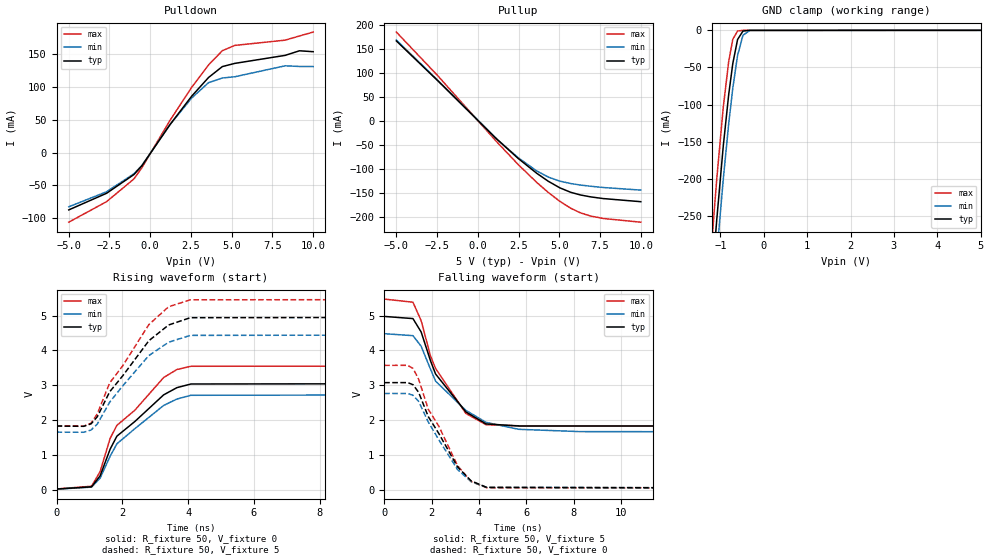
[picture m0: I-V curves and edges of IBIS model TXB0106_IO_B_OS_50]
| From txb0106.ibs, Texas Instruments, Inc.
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[Model]   TXB0106_IO_B_OS_50
Model_type  I/O
Vinl=1.575
Vinh=3.575
Enable   Active-High
Vref =   0
Rref =   1e6
Cref =   15p
Vmeas =   2.5
| variable   typ   min   max
C_comp   13.18pF   11.07pF   15.52pF
| C_pullup   13.01pF   10.37pF   16.24pF
| C_pulldown   13.28pF   11.92pF   15.14pF
| C_tri-state   13.18pF   11.07pF   15.52pF
[Temperature Range]   40   100   -40
| Ambient temperature   25   85   -40
[Voltage range]   5   4.5   5.5
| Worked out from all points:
|   slope of the pulldown table from 0 to 0.75 V, typ, clamps not added: 27.3 ohm
|   slope of the pullup table from 0 to 0.75 V, typ, clamps not added: 29.6 ohm
|   GND clamp passes 1 mA (typ) near -0.48 V on its own axis
|   rising waveform, R_fixture 50, V_fixture 0: 20-80 % time 1.49ns typ, 1.5ns min, 1.47ns max; typ from 0.021 V to 3.08 V
|   falling waveform, R_fixture 50, V_fixture 5: 20-80 % time 1.5ns typ, 1.86ns min, 1.45ns max; typ from 4.98 V to 1.83 V
|   rising waveform, R_fixture 50, V_fixture 5: 20-80 % time 1.45ns typ, 1.44ns min, 1.42ns max; typ from 1.83 V to 4.98 V
|   falling waveform, R_fixture 50, V_fixture 0: 20-80 % time 1.47ns typ, 1.42ns min, 1.46ns max; typ from 3.08 V to 0.021 V
[GND Clamp]
| TXB0104_IO_B_OS_50
|   Voltage   I(typ)   I(min)   I(max)
-5V       -4.543A    -4.41A     -4.793A
-1.245V   -376.1mA   -424.3mA   -324mA
-1.21V    -348.4mA   -396.7mA   -295.4mA
-1.14V    -294.9mA   -343.1mA   -240.7mA
-1.085V   -254.9mA   -302.6mA   -200.3mA
-935mV    -155.8mA   -200.5mA   -103.7mA
-810mV    -86.64mA   -126.1mA   -42.07mA
-715mV    -44.62mA   -77.69mA   -11.99mA
-605mV    -12.35mA   -33.78mA   -908.3uA
-480mV    -968.2uA   -6.599mA   -13.77uA
-325mV    -13.63uA   -271.7uA   -22.36nA
5V        1.525nA    314.6nA    140.3pA
[Pulldown]
| TXB0104_IO_B_OS_50
|   Voltage   I(typ)   I(min)   I(max)
-5V       -87.47mA   -82.76mA   -106.2mA
-2.675V   -62.09mA   -59.78mA   -74.83mA
-1V       -33.59mA   -32.37mA   -40.27mA
-510mV    -20.09mA   -19.73mA   -23.11mA
1.21V     42.51mA    42.31mA    48.84mA
2.55V     86.05mA    83.26mA    99.58mA
3.58V     114.4mA    106.5mA    133.5mA
4.425V    131mA      113.6mA    155.2mA
5.19V     135.9mA    115.5mA    163.3mA
8.28V     148.1mA    132.2mA    171.3mA
9.16V     155.1mA    131.2mA    177.7mA
10V       153.7mA    131.1mA    183.6mA
[Pullup]
| TXB0104_IO_B_OS_50
|   Voltage   I(typ)   I(min)   I(max)
-5V       167.3mA    169.2mA    185.8mA
-2.47V    84.58mA    85.55mA    95.09mA
1.16V     -37.5mA    -37.56mA   -43.27mA
2.475V    -77.97mA   -76.43mA   -90.69mA
3.615V    -109mA     -104.1mA   -128.1mA
4.33V     -125.8mA   -117mA     -149.2mA
5.035V    -139.4mA   -125.4mA   -167.6mA
5.7V      -148.7mA   -130.4mA   -182mA
6.305V    -154.3mA   -133.6mA   -191.7mA
6.93V     -158.3mA   -136.1mA   -198.3mA
7.705V    -161.8mA   -138.7mA   -203.4mA
10V       -168.3mA   -144.1mA   -211.1mA
[Ramp]
| TXB0104_IO_B_OS_50
| variable   typ   min   max
dV/dt_r   1.84/1.49E-09   1.65/1.50E-09   2.14/1.47E-09
dV/dt_f   1.89/1.50E-09   1.70/1.86E-09   2.19/1.45E-09
R_load = 50
[Rising Waveform]
| TXB0104_IO_B_OS_50
R_fixture =   50
C_fixture =   0
L_fixture =   0
V_fixture =   0
V_fixture_min = 0
V_fixture_max = 0
|   Time   V(typ)   V(min)   V(max)
0s        20.61mV    17.19mV    22.19mV
1.065ns   85.01mV    76.13mV    102.1mV
1.325ns   400.5mV    333.6mV    521mV
1.63ns    1.168V     965.7mV    1.478V
1.835ns   1.54V      1.32V      1.85V
2.38ns    1.96V      1.754V     2.285V
3.255ns   2.725V     2.421V     3.223V
3.66ns    2.933V     2.606V     3.454V
4.085ns   3.037V     2.713V     3.546V
39.89ns   3.076V     2.765V     3.572V
[Falling Waveform]
| TXB0104_IO_B_OS_50
R_fixture =   50
C_fixture =   0
L_fixture =   0
V_fixture =   5
V_fixture_min = 4.5
V_fixture_max = 5.5
|   Time   V(typ)   V(min)   V(max)
0s        4.978V     4.482V     5.476V
1.215ns   4.915V     4.425V     5.385V
1.56ns    4.532V     4.122V     4.857V
1.955ns   3.704V     3.463V     3.842V
2.17ns    3.323V     3.119V     3.481V
3.445ns   2.236V     2.281V     2.193V
4.3ns     1.891V     1.935V     1.867V
5.67ns    1.832V     1.736V     1.837V
8.255ns   1.83V      1.67V      1.836V
39.89ns   1.83V      1.655V     1.836V
[Rising Waveform]
| TXB0104_IO_B_OS_50
R_fixture =   50
C_fixture =   0
L_fixture =   0
V_fixture =   5
V_fixture_min = 4.5
V_fixture_max = 5.5
|   Time   V(typ)   V(min)   V(max)
0s        1.83V      1.655V     1.836V
825ps     1.822V     1.651V     1.825V
1.05ns    1.894V     1.716V     1.913V
1.24ns    2.098V     1.887V     2.182V
1.615ns   2.813V     2.515V     3.068V
2.01ns    3.27V      2.982V     3.557V
2.805ns   4.279V     3.853V     4.742V
3.405ns   4.731V     4.236V     5.255V
4.065ns   4.941V     4.433V     5.455V
39.89ns   4.978V     4.482V     5.476V
[Falling Waveform]
| TXB0104_IO_B_OS_50
R_fixture =   50
C_fixture =   0
L_fixture =   0
V_fixture =   0
V_fixture_min = 0
V_fixture_max = 0
|   Time   V(typ)   V(min)   V(max)
0s        3.076V     2.765V     3.572V
990ps     3.077V     2.765V     3.573V
1.22ns    3.016V     2.712V     3.483V
1.455ns   2.797V     2.537V     3.174V
1.86ns    2.102V     1.947V     2.314V
2.31ns    1.611V     1.431V     1.82V
3.095ns   657.9mV    579.7mV    693.3mV
3.665ns   256.5mV    234.7mV    238mV
4.32ns    69.52mV    68.52mV    58.33mV
39.89ns   20.62mV    17.19mV    22.19mV
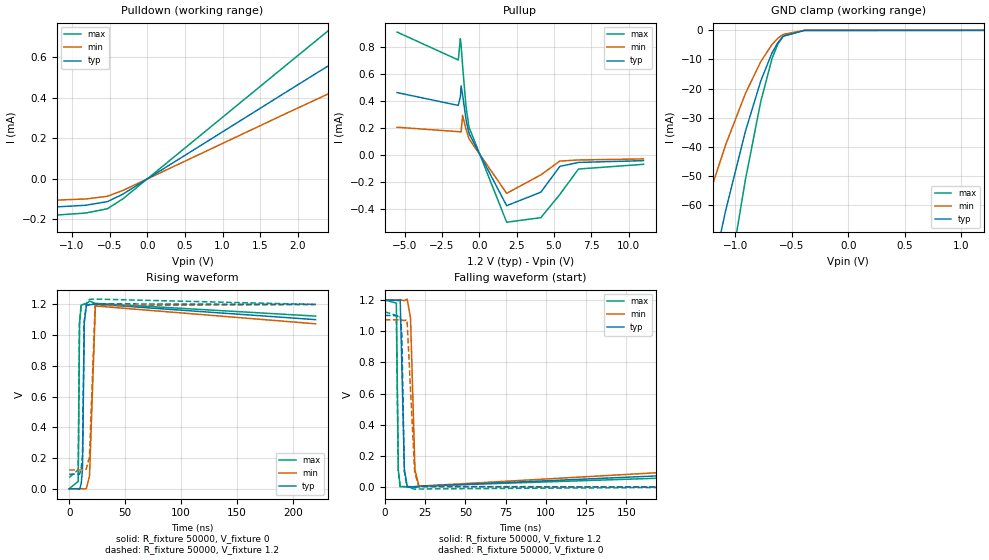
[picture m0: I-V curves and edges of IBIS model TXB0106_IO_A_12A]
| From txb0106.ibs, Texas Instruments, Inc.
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[Model]   TXB0106_IO_A_12A
Model_type  I/O
Vinl=0.42
Vinh=0.78
Enable   Active-High
Vref =   0
Rref =   1e6
Cref =   15p
Vmeas =   0.6
| variable   typ   min   max
C_comp   5.40pF   4.63pF   5.88pF
| C_pullup   5.28pF   4.58pF   5.68pF
| C_pulldown   5.26pF   4.58pF   5.61pF
| C_tri-state   5.40pF   4.63pF   5.88pF
[Temperature Range]   40   100   -40
| Ambient temperature   25   85   -40
[Voltage range]   1.2   1.2   1.2
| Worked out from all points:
|   slope of the pulldown table from 0 to 0.18 V, typ, clamps not added: 4.3 kohm
|   slope of the pullup table from 0 to 0.18 V, typ, clamps not added: 4.51 kohm
|   GND clamp passes 1 mA (typ) near -0.54 V on its own axis
|   rising waveform, R_fixture 50000, V_fixture 0: 20-80 % time 925ps typ, 1.45ns min, 577ps max; typ from 0 V to 1.1 V
|   falling waveform, R_fixture 50000, V_fixture 1.2: 20-80 % time 945ps typ, 1.58ns min, 563ps max; typ from 1.2 V to 0.095 V
|   rising waveform, R_fixture 50000, V_fixture 1.2: 20-80 % time 994ps typ, 1.58ns min, 608ps max; typ from 0.095 V to 1.2 V
|   falling waveform, R_fixture 50000, V_fixture 0: 20-80 % time 992ps typ, 1.68ns min, 585ps max; typ from 1.1 V to 0 V
[GND Clamp]
| TXB0104_IO_A_12A
|   Voltage   I(typ)   I(min)   I(max)
-5.5V     -1.185A    -900.4mA   -1.495A
-1.505V   -142.6mA   -93.49mA   -206.9mA
-1.46V    -133.1mA   -86.99mA   -193.8mA
-1.245V   -90.37mA   -58.09mA   -133.6mA
-1.085V   -61.77mA   -39.21mA   -91.98mA
-910mV    -34.58mA   -21.63mA   -51.1mA
-775mV    -17.41mA   -10.76mA   -24.5mA
-675mV    -7.745mA   -4.84mA    -9.681mA
-625mV    -4.315mA   -2.776mA   -4.834mA
-575mV    -2.026mA   -1.372mA   -1.96mA
-390mV    -29.93uA   -30.24uA   -11.62uA
1.2V      205.7pA    685.4pA    41.36pA
[Pulldown]
| TXB0104_IO_A_12A
|   Voltage   I(typ)   I(min)   I(max)
-5.5V     -174uA     -129.2uA   -231uA
-3.99V    -166.7uA   -124.1uA   -220uA
-1.675V   -148.2uA   -111.4uA   -191uA
-815mV    -130.1uA   -99.13uA   -168.4uA
-530mV    -112.3uA   -85.81uA   -147.4uA
-320mV    -74.53uA   -56.43uA   -97.58uA
1.875V    435.9uA    328.6uA    571uA
2.715V    629.9uA    473.2uA    825.9uA
3.405V    788.3uA    589.5uA    1.035mA
4.315V    995.4uA    735uA      1.309mA
4.615V    1.063mA    777.5uA    1.4mA
11V       2.022mA    1.154mA    3.037mA
[Pullup]
| TXB0104_IO_A_12A
|   Voltage   I(typ)   I(min)   I(max)
-5.5V     463uA      205.9uA    912uA
-1.405V   368uA      173.3uA    705uA
-1.265V   432.2uA    171.5uA    863uA
-1.215V   513.3uA    171.2uA    810.4uA
-1.115V   444.9uA    294.4uA    660.1uA
-885mV    261.9uA    189.8uA    356.5uA
-680mV    157.3uA    118.7uA    204.2uA
1.835V    -376.2uA   -284.4uA   -498.5uA
4.125V    -275.7uA   -147.4uA   -464.9uA
5.4V      -84.3uA    -44.9uA    -292uA
6.645V    -55uA      -36.9uA    -104uA
11V       -42uA      -29uA      -69uA
[Ramp]
| TXB0104_IO_A_12A
| variable   typ   min   max
dV/dt_r   0.73/1.06E-09   0.73/1.68E-09   0.74/6.53E-10
dV/dt_f   0.72/1.04E-09   0.72/1.77E-09   0.72/6.10E-10
R_load = 50000
[Rising Waveform]
| TXB0104_IO_A_12A
R_fixture =   50000
C_fixture =   0
L_fixture =   0
V_fixture =   0
V_fixture_min = 0
V_fixture_max = 0
|   Time   V(typ)   V(min)   V(max)
0s        225.1nV    1.703uV    17.34nV
8.04ns    387.8uV    5.668uV    48.18mV
9.2ns     -2.684mV   -8.585uV   1.074V
10.68ns   32.66mV    -52.66uV   1.196V
11.84ns   123mV      484.8uV    1.198V
13.45ns   1.08V      -1.675mV   1.201V
15.33ns   1.193V     2.37mV     1.204V
18.15ns   1.198V     84.59mV    1.222V
23.34ns   1.202V     1.19V      1.207V
220ns     1.101V     1.074V     1.124V
[Falling Waveform]
| TXB0104_IO_A_12A
R_fixture =   50000
C_fixture =   0
L_fixture =   0
V_fixture =   1.2
V_fixture_min = 1.2
V_fixture_max = 1.2
|   Time   V(typ)   V(min)   V(max)
0s        1.2V       1.2V       1.2V
7.16ns    1.198V     1.2V       1.18V
8.39ns    1.196V     1.2V       108.7mV
9.54ns    1.203V     1.2V       2.36mV
12.16ns   110.7mV    1.196V     2.709mV
13.89ns   3.286mV    1.206V     1.009mV
15.97ns   1.338mV    1.083V     -1.257mV
18.71ns   2.526mV    109.3mV    -3.655mV
21.28ns   4.343mV    5.563mV    5.939mV
220ns     94.66mV    121.6mV    73.79mV
[Rising Waveform]
| TXB0104_IO_A_12A
R_fixture =   50000
C_fixture =   0
L_fixture =   0
V_fixture =   1.2
V_fixture_min = 1.2
V_fixture_max = 1.2
|   Time   V(typ)   V(min)   V(max)
0s        94.74mV    122.1mV    73.82mV
8.035ns   95.15mV    122.1mV    123.4mV
9.16ns    93.28mV    122.1mV    1.082V
10.62ns   130.3mV    122mV      1.196V
11.82ns   212.1mV    122.6mV    1.199V
13.37ns   1.092V     121.3mV    1.202V
15.22ns   1.195V     128mV      1.206V
18.1ns    1.2V       207.6mV    1.233V
23.11ns   1.204V     1.192V     1.235V
220ns     1.2V       1.2V       1.2V
[Falling Waveform]
| TXB0104_IO_A_12A
R_fixture =   50000
C_fixture =   0
L_fixture =   0
V_fixture =   0
V_fixture_min = 0
V_fixture_max = 0
|   Time   V(typ)   V(min)   V(max)
0s        1.101V     1.073V     1.124V
7.155ns   1.1V       1.073V     1.101V
8.345ns   1.096V     1.073V     108.4mV
9.49ns    1.101V     1.073V     1.754mV
10.59ns   972.2mV    1.071V     2.224mV
12.09ns   101.8mV    1.068V     2.091mV
13.79ns   2.171mV    1.073V     453.5uV
18.52ns   2.451mV    98.22mV    -13.73mV
21.03ns   2.024mV    3.617mV    -12.38mV
220ns     -2.11uV    -59.05uV   8.332uV
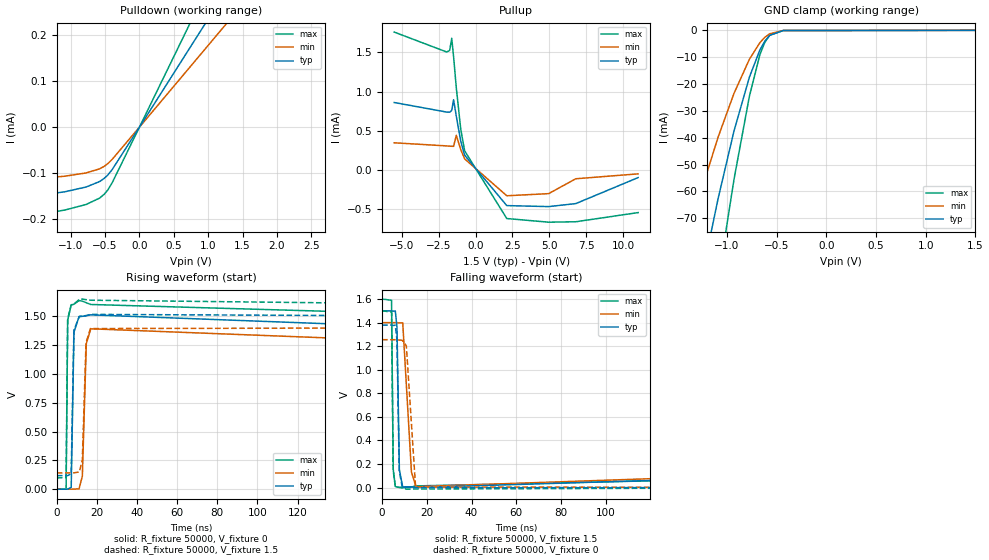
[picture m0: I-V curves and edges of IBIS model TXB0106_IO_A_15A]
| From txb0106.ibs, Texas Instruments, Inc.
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[Model]   TXB0106_IO_A_15A
Model_type  I/O
Vinl=0.49
Vinh=1.04
Enable   Active-High
Vref =   0
Rref =   1e6
Cref =   15p
Vmeas =   0.75
| variable   typ   min   max
C_comp   5.37pF   4.58pF   5.84pF
| C_pullup   5.26pF   4.57pF   5.68pF
| C_pulldown   8.81pF   4.57pF   24.32pF
| C_tri-state   5.37pF   4.58pF   5.84pF
[Temperature Range]   40   100   -40
| Ambient temperature   25   85   -40
[Voltage range]   1.5   1.4   1.6
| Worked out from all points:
|   slope of the pulldown table from 0 to 0.225 V, typ, clamps not added: 4.25 kohm
|   slope of the pullup table from 0 to 0.225 V, typ, clamps not added: 4.38 kohm
|   GND clamp passes 1 mA (typ) near -0.54 V on its own axis
|   rising waveform, R_fixture 50000, V_fixture 0: 20-80 % time 595ps typ, 1.04ns min, 335ps max; typ from 0 V to 1.38 V
|   falling waveform, R_fixture 50000, V_fixture 1.5: 20-80 % time 614ps typ, 1.13ns min, 337ps max; typ from 1.5 V to 0.117 V
|   rising waveform, R_fixture 50000, V_fixture 1.5: 20-80 % time 653ps typ, 1.15ns min, 362ps max; typ from 0.117 V to 1.5 V
|   falling waveform, R_fixture 50000, V_fixture 0: 20-80 % time 656ps typ, 1.22ns min, 355ps max; typ from 1.38 V to 0 V
[GND Clamp]
| TXB0104_IO_A_15A
|   Voltage   I(typ)   I(min)   I(max)
-5.5V     -1.185A    -900.5mA   -1.495A
-1.51V    -143.7mA   -94.25mA   -208.4mA
-1.275V   -96.1mA    -61.91mA   -141.8mA
-1.23V    -87.59mA   -56.24mA   -129.6mA
-1.09V    -62.64mA   -39.78mA   -93.27mA
-930mV    -37.46mA   -23.47mA   -55.48mA
-775mV    -17.42mA   -10.77mA   -24.52mA
-670mV    -7.359mA   -4.607mA   -9.114mA
-620mV    -4.037mA   -2.607mA   -4.464mA
-570mV    -1.86mA    -1.268mA   -1.771mA
-435mV    -97.8uA    -86.16uA   -51.85uA
1.5V      245.4pA    3.258nA    46.9pA
[Pulldown]
| TXB0104_IO_A_15A
|   Voltage   I(typ)   I(min)   I(max)
-5.5V     -185uA     -137uA     -243uA
-3.15V    -168uA     -125.7uA   -217.7uA
-1.535V   -149.7uA   -112.9uA   -191.7uA
-1.085V   -140.6uA   -106.7uA   -180.3uA
-775mV    -130.2uA   -99.57uA   -168.2uA
-580mV    -118.4uA   -90.76uA   -154.4uA
-510mV    -111.2uA   -85.04uA   -145.7uA
-455mV    -103.3uA   -78.71uA   -135.6uA
-395mV    -91.95uA   -69.85uA   -120.5uA
0V        0A         0A         0A
2.78V     654uA      494.7uA    853.5uA
11V       2.552mA    1.58mA     3.361mA
[Pullup]
| TXB0104_IO_A_15A
|   Voltage   I(typ)   I(min)   I(max)
-5.5V     859.3uA    344.7uA    1.759mA
-1.955V   737.2uA    304.9uA    1.505mA
-1.75V    735.9uA    302uA      1.525mA
-1.61V    758.9uA    300.1uA    1.68mA
-1.485V   894.2uA    299.7uA    1.446mA
-1.3V     682.2uA    440.4uA    1.046mA
-1V       365uA      257.9uA    518.5uA
-735mV    185.9uA    138.7uA    241.5uA
2.115V    -457.7uA   -332uA     -622.8uA
4.945V    -470.3uA   -304.9uA   -669.6uA
6.785V    -432uA     -114.8uA   -664uA
11V       -100uA     -52uA      -547uA
[Ramp]
| TXB0104_IO_A_15A
| variable   typ   min   max
dV/dt_r   0.92/7.02E-10   0.85/1.23E-09   0.98/3.90E-10
dV/dt_f   0.90/6.82E-10   0.84/1.28E-09   0.96/3.76E-10
R_load = 50000
[Rising Waveform]
| TXB0104_IO_A_15A
R_fixture =   50000
C_fixture =   0
L_fixture =   0
V_fixture =   0
V_fixture_min = 0
V_fixture_max = 0
|   Time   V(typ)   V(min)   V(max)
0s        257.7nV    1.766uV    23.2nV
4.59ns    -58.09uV   15.87uV    4.033mV
5.385ns   552.8uV    9.35uV     1.466V
7.13ns    14.71mV    -38.47uV   1.598V
8.515ns   1.362V     561.6uV    1.604V
11.05ns   1.497V     2.772mV    1.636V
12.69ns   1.499V     113.2mV    1.631V
14.66ns   1.504V     1.263V     1.617V
16.91ns   1.512V     1.391V     1.602V
220ns     1.379V     1.255V     1.5V
[Falling Waveform]
| TXB0104_IO_A_15A
R_fixture =   50000
C_fixture =   0
L_fixture =   0
V_fixture =   1.5
V_fixture_min = 1.4
V_fixture_max = 1.6
|   Time   V(typ)   V(min)   V(max)
0s        1.5V       1.4V       1.6V
4.25ns    1.5V       1.4V       1.59V
4.995ns   1.497V     1.4V       155.5mV
5.94ns    1.499V     1.4V       8.804mV
6.68ns    1.358V     1.4V       4.737mV
7.74ns    150.8mV    1.397V     1.661mV
9.25ns    4.779mV    1.398V     -1.378mV
13.14ns   5.285mV    132.3mV    4.553mV
15.17ns   -48.49uV   6.669mV    13.81mV
220ns     117.3mV    140.4mV    97.75mV
[Rising Waveform]
| TXB0104_IO_A_15A
R_fixture =   50000
C_fixture =   0
L_fixture =   0
V_fixture =   1.5
V_fixture_min = 1.4
V_fixture_max = 1.6
|   Time   V(typ)   V(min)   V(max)
0s        117.3mV    140.8mV    97.77mV
4.585ns   117.3mV    140.8mV    100.9mV
5.37ns    117.9mV    140.8mV    1.477V
7.115ns   131.6mV    140.8mV    1.599V
8.49ns    1.38V      141.4mV    1.605V
11.21ns   1.499V     149.6mV    1.647V
12.67ns   1.501V     253.3mV    1.649V
14.51ns   1.506V     1.27V      1.644V
16.72ns   1.516V     1.393V     1.639V
220ns     1.5V       1.4V       1.6V
[Falling Waveform]
| TXB0104_IO_A_15A
R_fixture =   50000
C_fixture =   0
L_fixture =   0
V_fixture =   0
V_fixture_min = 0
V_fixture_max = 0
|   Time   V(typ)   V(min)   V(max)
0s        1.379V     1.255V     1.5V
4.25ns    1.379V     1.255V     1.49V
4.98ns    1.376V     1.255V     144.8mV
5.925ns   1.378V     1.255V     7.909mV
6.66ns    1.254V     1.255V     3.887mV
7.69ns    142.3mV    1.252V     1.025mV
8.995ns   4.897mV    1.25V      -1.936mV
10.86ns   3.931mV    1.203V     -13.76mV
14.99ns   -1.549mV   4.755mV    -12.77mV
220ns     9.536uV    -35.66uV   28.91uV
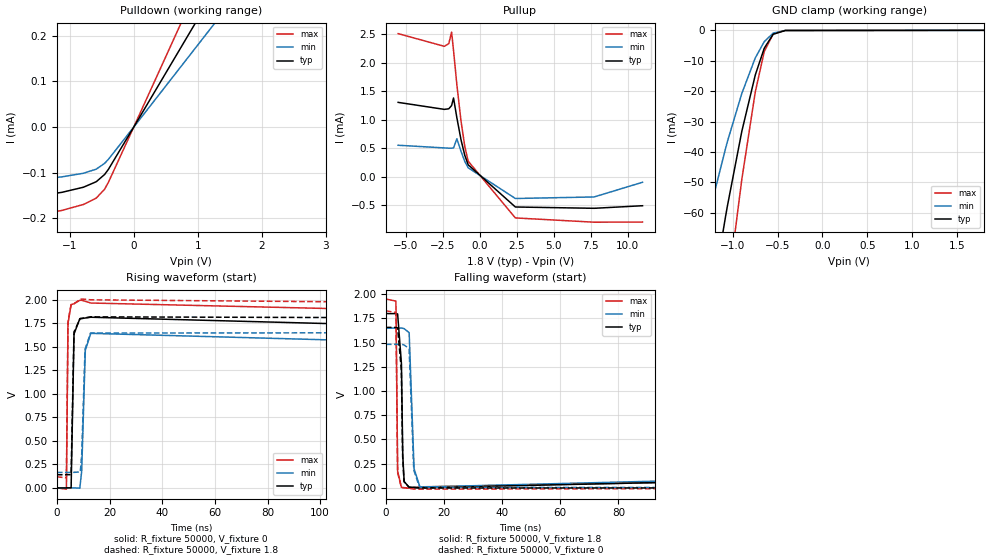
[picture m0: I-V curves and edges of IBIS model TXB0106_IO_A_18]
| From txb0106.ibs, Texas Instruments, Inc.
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[Model]   TXB0106_IO_A_18
Model_type  I/O
Vinl=0.5775
Vinh=1.2675
Enable   Active-High
Vref =   0
Rref =   1e6
Cref =   15p
Vmeas =   0.9
| variable   typ   min   max
C_comp   5.33pF   4.55pF   5.74pF
| C_pullup   5.23pF   4.52pF   5.58pF
| C_pulldown   11.19pF   4.52pF   29.20pF
| C_tri-state   5.33pF   4.55pF   5.74pF
[Temperature Range]   40   100   -40
| Ambient temperature   25   85   -40
[Voltage range]   1.8   1.65   1.95
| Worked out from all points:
|   slope of the pulldown table from 0 to 0.27 V, typ, clamps not added: 4.23 kohm
|   slope of the pullup table from 0 to 0.27 V, typ, clamps not added: 4.32 kohm
|   GND clamp passes 1 mA (typ) near -0.54 V on its own axis
|   rising waveform, R_fixture 50000, V_fixture 0: 20-80 % time 457ps typ, 787ps min, 267ps max; typ from 0 V to 1.66 V
|   falling waveform, R_fixture 50000, V_fixture 1.8: 20-80 % time 471ps typ, 850ps min, 266ps max; typ from 1.8 V to 0.14 V
|   rising waveform, R_fixture 50000, V_fixture 1.8: 20-80 % time 508ps typ, 886ps min, 292ps max; typ from 0.14 V to 1.8 V
|   falling waveform, R_fixture 50000, V_fixture 0: 20-80 % time 510ps typ, 931ps min, 285ps max; typ from 1.66 V to 0 V
[GND Clamp]
| TXB0104_IO_A_18
|   Voltage   I(typ)   I(min)   I(max)
-5.5V     -1.185A    -900.6mA   -1.495A
-1.48V    -137.4mA   -89.92mA   -199.7mA
-1.245V   -90.43mA   -58.13mA   -133.7mA
-1.22V    -85.75mA   -55.02mA   -127mA
-1.08V    -60.97mA   -38.7mA    -90.79mA
-1.06V    -57.64mA   -36.52mA   -85.85mA
-900mV    -33.21mA   -20.75mA   -48.99mA
-750mV    -14.72mA   -9.092mA   -20.3mA
-650mV    -5.9mA     -3.73mA    -7.017mA
-550mV    -1.294mA   -906.8uA   -1.153mA
-415mV    -58.42uA   -54.48uA   -27.18uA
1.8V      288.8pA    2.007nA    56.61pA
[Pulldown]
| TXB0104_IO_A_18
|   Voltage   I(typ)   I(min)   I(max)
-5.5V     -191uA     -143.5uA   -246uA
-4V       -179.1uA   -135.3uA   -231uA
-2.535V   -165.2uA   -125.1uA   -211.2uA
-1.58V    -152.3uA   -115.7uA   -194uA
-1.125V   -142.9uA   -109uA     -182.5uA
-785mV    -131.6uA   -101uA     -169.4uA
-585mV    -119.5uA   -91.96uA   -155.4uA
-455mV    -103.8uA   -79.39uA   -136uA
-395mV    -92.41uA   -70.45uA   -120.8uA
0V        0A         0A         0A
3.795V    897.8uA    682.3uA    1.169mA
11V       2.592mA    1.946mA    3.38mA
[Pullup]
| TXB0104_IO_A_18
|   Voltage   I(typ)   I(min)   I(max)
-5.5V     1.303mA    550uA      2.51mA
-2.38V    1.18mA     503.1uA    2.287mA
-2.08V    1.19mA     498.8uA    2.334mA
-1.89V    1.247mA    498.4uA    2.537mA
-1.76V    1.38mA     502.6uA    2.214mA
-1.535V   1.033mA    663.1uA    1.612mA
-1.255V   645.9uA    444.1uA    976.2uA
-1V       372.8uA    265.4uA    528.5uA
-770mV    206.9uA    154.1uA    269.6uA
2.415V    -534.2uA   -384.9uA   -726.2uA
7.73V     -557uA     -358uA     -801uA
11V       -512uA     -100uA     -798uA
[Ramp]
| TXB0104_IO_A_18
| variable   typ   min   max
dV/dt_r   1.11/5.50E-10   1.01/9.51E-10   1.21/3.19E-10
dV/dt_f   1.08/5.32E-10   0.99/9.73E-10   1.17/3.03E-10
R_load = 50000
[Rising Waveform]
| TXB0104_IO_A_18
R_fixture =   50000
C_fixture =   0
L_fixture =   0
V_fixture =   0
V_fixture_min = 0
V_fixture_max = 0
|   Time   V(typ)   V(min)   V(max)
0s        294.7nV    1.858uV    28.68nV
3.605ns   -56.8uV    17.46uV    -13.33mV
4.22ns    554.4uV    16.01uV    1.747V
5.4ns     968.3uV    -40.27uV   1.946V
6.505ns   1.634V     630.9uV    1.955V
8.7ns     1.797V     -3mV       1.992V
9.415ns   1.798V     180.1mV    1.992V
10.79ns   1.804V     1.462V     1.981V
12.87ns   1.812V     1.641V     1.963V
220ns     1.657V     1.482V     1.829V
[Falling Waveform]
| TXB0104_IO_A_18
R_fixture =   50000
C_fixture =   0
L_fixture =   0
V_fixture =   1.8
V_fixture_min = 1.65
V_fixture_max = 1.95
|   Time   V(typ)   V(min)   V(max)
0s        1.8V       1.65V      1.95V
3.445ns   1.8V       1.65V      1.929V
4.03ns    1.796V     1.65V      172.4mV
5.335ns   1.285V     1.65V      5.038mV
5.795ns   336.4mV    1.648V     2.549mV
6.275ns   65.16mV    1.644V     1.344mV
7.995ns   4.319mV    1.603V     -4.006mV
9.675ns   6.457mV    198.1mV    -1.173mV
11.71ns   -657uV     7.568mV    9.897mV
220ns     140.1mV    164.3mV    118.8mV
[Rising Waveform]
| TXB0104_IO_A_18
R_fixture =   50000
C_fixture =   0
L_fixture =   0
V_fixture =   1.8
V_fixture_min = 1.65
V_fixture_max = 1.95
|   Time   V(typ)   V(min)   V(max)
0s        140.1mV    164.7mV    118.8mV
3.605ns   140.1mV    164.7mV    105.4mV
4.215ns   140.7mV    164.7mV    1.769V
5.39ns    139.7mV    164.6mV    1.947V
6.49ns    1.656V     165.3mV    1.956V
8.88ns    1.799V     169.3mV    2.003V
9.425ns   1.8V       355.3mV    2.005V
10.68ns   1.806V     1.471V     2.003V
12.76ns   1.816V     1.644V     1.997V
220ns     1.8V       1.65V      1.95V
[Falling Waveform]
| TXB0104_IO_A_18
R_fixture =   50000
C_fixture =   0
L_fixture =   0
V_fixture =   0
V_fixture_min = 0
V_fixture_max = 0
|   Time   V(typ)   V(min)   V(max)
0s        1.657V     1.482V     1.829V
3.445ns   1.657V     1.482V     1.81V
4.02ns    1.653V     1.482V     158.2mV
5.3ns     1.217V     1.481V     4.266mV
5.755ns   323mV      1.48V      1.826mV
6.225ns   62.89mV    1.476V     649.2uV
7.975ns   6.476mV    1.439V     -6.401mV
9.58ns    2.282mV    185.4mV    -13.6mV
11.56ns   -2.32mV    5.642mV    -14.12mV
220ns     27.57uV    -14.83uV   33.89uV
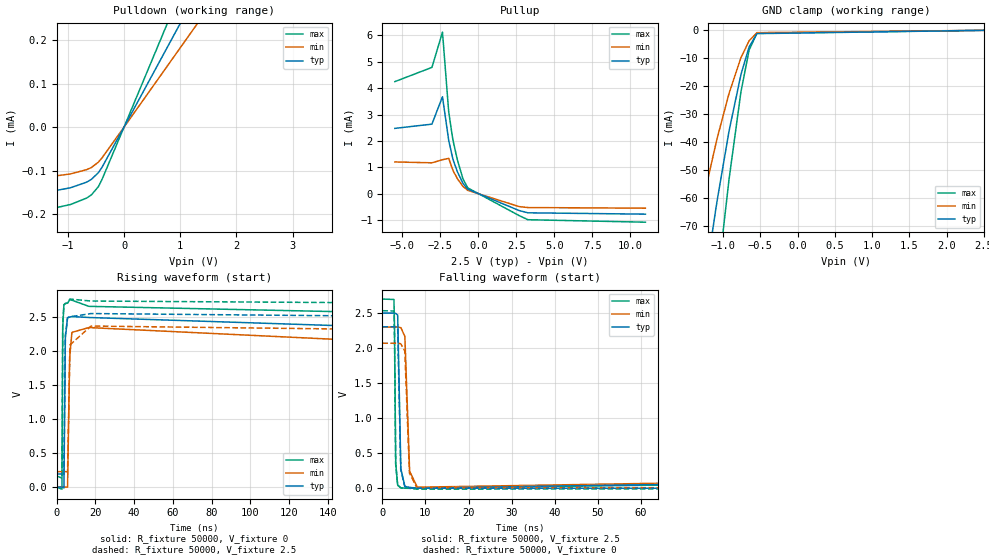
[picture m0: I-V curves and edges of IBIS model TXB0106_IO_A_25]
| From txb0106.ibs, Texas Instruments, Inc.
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[Model]   TXB0106_IO_A_25
Model_type  I/O
Vinl=0.805
Vinh=1.755
Enable   Active-High
Vref =   0
Rref =   1e6
Cref =   15p
Vmeas =   1.25
| variable   typ   min   max
C_comp   5.22pF   4.48pF   5.57pF
| C_pullup   5.15pF   4.45pF   5.71pF
| C_pulldown   13.58pF   3.89pF   27.06pF
| C_tri-state   5.22pF   4.48pF   5.57pF
[Temperature Range]   40   100   -40
| Ambient temperature   25   85   -40
[Voltage range]   2.5   2.3   2.7
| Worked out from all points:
|   slope of the pulldown table from 0 to 0.375 V, typ, clamps not added: 4.2 kohm
|   slope of the pullup table from 0 to 0.375 V, typ, clamps not added: 4.26 kohm
|   GND clamp passes 1 mA (typ) near -0.54 V on its own axis
|   rising waveform, R_fixture 50000, V_fixture 0: 20-80 % time 329ps typ, 516ps min, 194ps max; typ from 0 V to 2.3 V
|   falling waveform, R_fixture 50000, V_fixture 2.5: 20-80 % time 331ps typ, 549ps min, 191ps max; typ from 2.5 V to 0.194 V
|   rising waveform, R_fixture 50000, V_fixture 2.5: 20-80 % time 371ps typ, 598ps min, 211ps max; typ from 0.194 V to 2.5 V
|   falling waveform, R_fixture 50000, V_fixture 0: 20-80 % time 367ps typ, 624ps min, 206ps max; typ from 2.3 V to 0 V
[GND Clamp]
| TXB0104_IO_A_25
|   Voltage   I(typ)   I(min)   I(max)
-5.5V     -1.186A    -900.8mA   -1.496A
-1.515V   -144.9mA   -95.07mA   -210mA
-1.465V   -134.3mA   -87.81mA   -195.4mA
-1.27V    -95.21mA   -61.34mA   -140.5mA
-1.225V   -86.72mA   -55.68mA   -128.4mA
-1.095V   -63.54mA   -40.38mA   -94.57mA
-1.075V   -60.17mA   -38.18mA   -89.58mA
-920mV    -36.05mA   -22.57mA   -53.32mA
-760mV    -15.79mA   -9.759mA   -21.96mA
-650mV    -5.904mA   -3.734mA   -7.021mA
-545mV    -1.177mA   -831uA     -1.031mA
2.5V      406.8pA    1.876nA    81.51pA
[Pulldown]
| TXB0104_IO_A_25
|   Voltage   I(typ)   I(min)   I(max)
-5.5V     -198uA     -152.3uA   -252uA
-3.99V    -184uA     -141.8uA   -235uA
-3.315V   -177.2uA   -136.5uA   -225.5uA
-1.56V    -153.9uA   -118.2uA   -194.9uA
-950mV    -139uA     -107.2uA   -177.4uA
-665mV    -126.2uA   -97.61uA   -162.8uA
-580mV    -119.8uA   -92.66uA   -155.4uA
-455mV    -104.4uA   -80.21uA   -136.4uA
-390mV    -91.86uA   -70.33uA   -119.7uA
0V        0A         0A         0A
5.775V    1.374mA    1.051mA    1.783mA
11V       2.615mA    1.998mA    3.395mA
[Pullup]
| TXB0104_IO_A_25
|   Voltage   I(typ)   I(min)   I(max)
-5.5V     2.48mA     1.21mA     4.25mA
-3.06V    2.641mA    1.177mA    4.788mA
-2.365V   3.678mA    1.295mA    6.124mA
-1.955V   2.027mA    1.345mA    3.103mA
-1.7V     1.369mA    931.5uA    2.12mA
-1.63V    1.235mA    841.9uA    1.917mA
-1.39V    847.2uA    582.4uA    1.303mA
-1.015V   397uA      283.2uA    566.3uA
-700mV    178uA      135.2uA    228uA
2.685V    -629.8uA   -480.2uA   -820.3uA
3.26V     -714.9uA   -516uA     -976.1uA
11V       -766uA     -540uA     -1.07mA
[Ramp]
| TXB0104_IO_A_25
| variable   typ   min   max
dV/dt_r   1.55/4.07E-10   1.42/6.45E-10   1.68/2.31E-10
dV/dt_f   1.50/3.83E-10   1.38/6.48E-10   1.63/2.17E-10
R_load = 50000
[Rising Waveform]
| TXB0104_IO_A_25
R_fixture =   50000
C_fixture =   0
L_fixture =   0
V_fixture =   0
V_fixture_min = 0
V_fixture_max = 0
|   Time   V(typ)   V(min)   V(max)
0s        398.4nV    2.14uV     41.83nV
2.78ns    -114.6uV   -20.15uV   -29.86mV
3.205ns   844.8uV    -877.4nV   2.349V
3.805ns   -12.08mV   -98.07uV   2.679V
4.555ns   2.196V     1.222mV    2.699V
5.695ns   2.49V      -985.1uV   2.706V
6.77ns    2.499V     1.897V     2.753V
7.935ns   2.508V     2.275V     2.748V
16.7ns    2.494V     2.346V     2.658V
220ns     2.304V     2.069V     2.534V
[Falling Waveform]
| TXB0104_IO_A_25
R_fixture =   50000
C_fixture =   0
L_fixture =   0
V_fixture =   2.5
V_fixture_min = 2.3
V_fixture_max = 2.7
|   Time   V(typ)   V(min)   V(max)
0s        2.5V       2.3V       2.7V
2.69ns    2.5V       2.3V       2.694V
2.815ns   2.5V       2.3V       2.315V
3.1ns     2.494V     2.3V       354.3mV
3.555ns   2.472V     2.3V       43.65mV
4.29ns    276.4mV    2.292V     5.495mV
5.225ns   24.52mV    2.166V     -862.5uV
6.33ns    9.976mV    239.4mV    -1.486mV
8.13ns    -449.2uV   12.74mV    -275.8uV
220ns     193.6mV    227.2mV    164.1mV
[Rising Waveform]
| TXB0104_IO_A_25
R_fixture =   50000
C_fixture =   0
L_fixture =   0
V_fixture =   2.5
V_fixture_min = 2.3
V_fixture_max = 2.7
|   Time   V(typ)   V(min)   V(max)
0s        193.7mV    227.5mV    164.1mV
2.78ns    193.5mV    227.4mV    133.4mV
2.895ns   193.5mV    227.5mV    451.5mV
3.195ns   194.5mV    227.5mV    2.373V
3.795ns   176.9mV    227.4mV    2.681V
4.545ns   2.231V     228.7mV    2.701V
5.685ns   2.492V     224mV      2.708V
6.925ns   2.504V     2.091V     2.765V
17.77ns   2.552V     2.368V     2.736V
220ns     2.5V       2.3V       2.7V
[Falling Waveform]
| TXB0104_IO_A_25
R_fixture =   50000
C_fixture =   0
L_fixture =   0
V_fixture =   0
V_fixture_min = 0
V_fixture_max = 0
|   Time   V(typ)   V(min)   V(max)
0s        2.304V     2.069V     2.534V
2.69ns    2.304V     2.069V     2.529V
2.81ns    2.304V     2.069V     2.184V
3.09ns    2.3V       2.069V     334.7mV
3.555ns   2.28V      2.069V     39.4mV
4.265ns   260.6mV    2.062V     4.542mV
5.205ns   19.88mV    1.957V     -1.826mV
6.29ns    3.754mV    211.7mV    -3.008mV
7.995ns   -2.301mV   8.311mV    -15.18mV
220ns     44.75uV    35.36uV    34.86uV
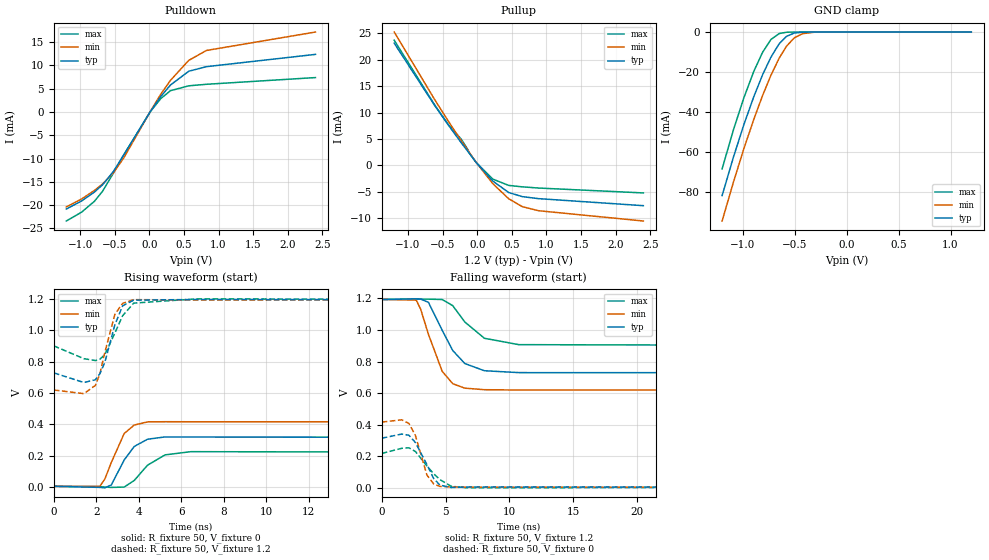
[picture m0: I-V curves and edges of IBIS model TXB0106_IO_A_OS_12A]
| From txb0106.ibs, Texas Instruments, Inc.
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[Model]   TXB0106_IO_A_OS_12A
Model_type  I/O
Vinl=0.42
Vinh=0.78
Enable   Active-High
Vref =   0
Rref =   1E6
Cref =   15p
Vmeas =   0.6
| variable   typ   min   max
C_comp   5.12pF   4.46pF   5.48pF
| C_pullup   6.07pF   4.23pF   7.10pF
| C_pulldown   6.15pF   5.13pF   7.44pF
| C_tri-state   5.12pF   4.46pF   5.48pF
[Temperature Range]   40   100   -40
| Ambient temperature   25   85   -40
[Voltage range]   1.2   1.2   1.2
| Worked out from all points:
|   slope of the pulldown table from 0 to 0.18 V, typ, clamps not added: 47 ohm
|   slope of the pullup table from 0 to 0.18 V, typ, clamps not added: 66.8 ohm
|   GND clamp passes 1 mA (typ) near -0.54 V on its own axis
|   rising waveform, R_fixture 50, V_fixture 0: 20-80 % time 787ps typ, 759ps min, 928ps max; typ from 0.006 V to 0.316 V
|   falling waveform, R_fixture 50, V_fixture 1.2: 20-80 % time 1.87ns typ, 1.51ns min, 1.99ns max; typ from 1.19 V to 0.729 V
|   rising waveform, R_fixture 50, V_fixture 1.2: 20-80 % time 561ps typ, 612ps min, 624ps max; typ from 0.729 V to 1.19 V
|   falling waveform, R_fixture 50, V_fixture 0: 20-80 % time 1.14ns typ, 880ps min, 1.45ns max; typ from 0.316 V to 0.006 V
[GND Clamp]
| TXB0104_IO_A_OS_12A
|   Voltage   I(typ)   I(min)   I(max)
-1.2V     -81.62mA   -94.33mA   -68.28mA
-1.09V    -62.29mA   -74.77mA   -48.65mA
-990mV    -46.14mA   -58.17mA   -32.73mA
-895mV    -32.28mA   -43.58mA   -19.66mA
-810mV    -21.32mA   -31.66mA   -10.1mA
-730mV    -12.55mA   -21.6mA    -3.745mA
-650mV    -5.818mA   -13mA      -764.2uA
-580mV    -2.162mA   -7.088mA   -111.2uA
-505mV    -499.9uA   -2.896mA   -9.159uA
-425mV    -73uA      -804.2uA   -417nA
-310mV    -2.844uA   -79.25uA   -3.133nA
1.2V      193pA      56.49nA    33.5pA
[Pulldown]
| TXB0104_IO_A_OS_12A
|   Voltage   I(typ)   I(min)   I(max)
-1.2V     -20.83mA   -20.38mA   -23.4mA
-980mV    -19.12mA   -18.69mA   -21.51mA
-795mV    -17.21mA   -16.87mA   -19.2mA
-675mV    -15.63mA   -15.45mA   -17mA
-515mV    -12.69mA   -13.01mA   -13.03mA
-365mV    -9.096mA   -9.761mA   -9.145mA
15mV      80.52uA    134.7uA    48.43uA
165mV     3.274mA    3.772mA    2.841mA
305mV     5.749mA    6.752mA    4.534mA
570mV     8.709mA    11.04mA    5.582mA
825mV     9.685mA    13.16mA    5.908mA
2.4V      12.32mA    17.11mA    7.348mA
[Pullup]
| TXB0104_IO_A_OS_12A
|   Voltage   I(typ)   I(min)   I(max)
-1.2V     23.15mA    25.26mA    23.71mA
-610mV    11.24mA    12.34mA    11.35mA
-420mV    7.673mA    8.408mA    7.766mA
-230mV    4.254mA    4.648mA    4.944mA
-130mV    2.534mA    2.734mA    2.868mA
-125mV    2.45mA     2.639mA    2.526mA
-15mV     534uA      540.6uA    541.2uA
225mV     -2.987mA   -3.48mA    -2.613mA
455mV     -5.154mA   -6.341mA   -3.808mA
650mV     -5.925mA   -7.824mA   -4.076mA
885mV     -6.312mA   -8.599mA   -4.302mA
2.4V      -7.643mA   -10.55mA   -5.227mA
[Ramp]
| TXB0104_IO_A_OS_12A
| variable   typ   min   max
dV/dt_r   0.20/8.38E-10   0.25/7.73E-10   0.14/1.02E-09
dV/dt_f   0.28/1.88E-09   0.35/1.51E-09   0.18/2.00E-09
R_load = 50
[Rising Waveform]
| TXB0104_IO_A_OS_12A
R_fixture =   50
C_fixture =   0
L_fixture =   0
V_fixture =   0
V_fixture_min = 0
V_fixture_max = 0
|   Time   V(typ)   V(min)   V(max)
0s        6.153mV    5.491mV    6.625mV
2.165ns   -657.2uV   6.121mV    4.159mV
2.4ns     -3.613mV   52.04mV    1.392mV
2.705ns   14.52mV    157.8mV    -899.9uV
3.31ns    173.5mV    342.2mV    1.254mV
3.785ns   260mV      396.3mV    43.49mV
4.41ns    306mV      416.4mV    140.6mV
5.235ns   320.7mV    417.6mV    206.4mV
6.45ns    319.9mV    417.3mV    226.8mV
39.96ns   315.5mV    417.3mV    219.1mV
[Falling Waveform]
| TXB0104_IO_A_OS_12A
R_fixture =   50
C_fixture =   0
L_fixture =   0
V_fixture =   1.2
V_fixture_min = 1.2
V_fixture_max = 1.2
|   Time   V(typ)   V(min)   V(max)
0s        1.192V     1.193V     1.192V
2.705ns   1.196V     1.188V     1.194V
3.045ns   1.195V     1.132V     1.194V
3.66ns    1.174V     971.7mV    1.194V
4.74ns    997.1mV    738mV      1.192V
5.565ns   869.7mV    659.9mV    1.153V
6.51ns    787.4mV    631.7mV    1.05V
8.045ns   741.8mV    622mV      947mV
10.74ns   730mV      619.9mV    906.7mV
39.96ns   728.7mV    619.7mV    900.7mV
[Rising Waveform]
| TXB0104_IO_A_OS_12A
R_fixture =   50
C_fixture =   0
L_fixture =   0
V_fixture =   1.2
V_fixture_min = 1.2
V_fixture_max = 1.2
|   Time   V(typ)   V(min)   V(max)
0s        728.7mV    619.6mV    900.6mV
1.415ns   667.2mV    596.3mV    819.1mV
1.955ns   684.8mV    648.9mV    807.2mV
2.17ns    723.7mV    723.4mV    815.6mV
2.4ns     795.8mV    859.2mV    844.7mV
2.875ns   1.036V     1.102V     983.2mV
3.24ns    1.156V     1.172V     1.093V
3.76ns    1.192V     1.195V     1.173V
6.735ns   1.196V     1.193V     1.2V
39.96ns   1.192V     1.193V     1.192V
[Falling Waveform]
| TXB0104_IO_A_OS_12A
R_fixture =   50
C_fixture =   0
L_fixture =   0
V_fixture =   0
V_fixture_min = 0
V_fixture_max = 0
|   Time   V(typ)   V(min)   V(max)
0s        315.5mV    417.3mV    219.1mV
1.57ns    341.6mV    431.6mV    251.6mV
2.13ns    334.1mV    408.9mV    254.8mV
2.635ns   288.7mV    333.6mV    231.7mV
3.54ns    148.9mV    82.63mV    140mV
4.07ns    60.83mV    25.96mV    91.02mV
4.56ns    19.2mV     10.74mV    53.71mV
5.44ns    3.789mV    7.228mV    11.88mV
6.705ns   7.13mV     6.072mV    1.716mV
39.96ns   6.153mV    5.491mV    6.625mV
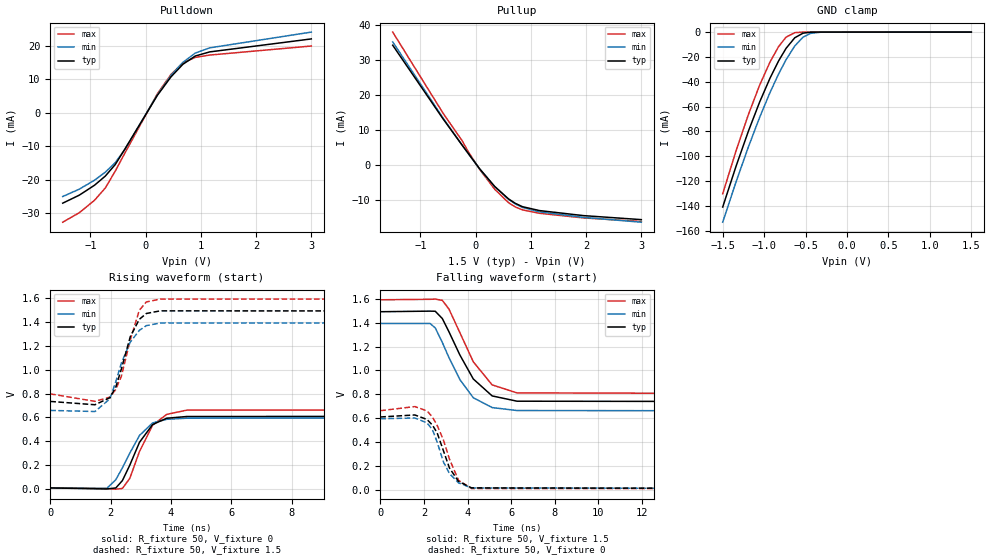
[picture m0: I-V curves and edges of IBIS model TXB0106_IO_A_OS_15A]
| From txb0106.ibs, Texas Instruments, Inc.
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[Model]   TXB0106_IO_A_OS_15A
Model_type  I/O
Vinl=0.49
Vinh=1.04
Enable   Active-High
Vref =   0
Rref =   1E6
Cref =   15p
Vmeas =   0.75
| variable   typ   min   max
C_comp   5.11pF   4.37pF   5.52pF
| C_pullup   5.88pF   4.01pF   7.20pF
| C_pulldown   5.93pF   5.05pF   7.05pF
| C_tri-state   5.11pF   4.37pF   5.52pF
[Temperature Range]   40   100   -40
| Ambient temperature   25   85   -40
[Voltage range]   1.5   1.4   1.6
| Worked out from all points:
|   slope of the pulldown table from 0 to 0.225 V, typ, clamps not added: 38.3 ohm
|   slope of the pullup table from 0 to 0.225 V, typ, clamps not added: 50.5 ohm
|   GND clamp passes 1 mA (typ) near -0.54 V on its own axis
|   rising waveform, R_fixture 50, V_fixture 0: 20-80 % time 681ps typ, 760ps min, 664ps max; typ from 0.007 V to 0.61 V
|   falling waveform, R_fixture 50, V_fixture 1.5: 20-80 % time 1.34ns typ, 1.27ns min, 1.32ns max; typ from 1.49 V to 0.734 V
|   rising waveform, R_fixture 50, V_fixture 1.5: 20-80 % time 535ps typ, 630ps min, 470ps max; typ from 0.733 V to 1.49 V
|   falling waveform, R_fixture 50, V_fixture 0: 20-80 % time 760ps typ, 759ps min, 773ps max; typ from 0.61 V to 0.007 V
[GND Clamp]
| TXB0104_IO_A_OS_15A
|   Voltage   I(typ)   I(min)   I(max)
-1.5V     -141mA     -153.2mA   -130.3mA
-1.34V    -108.3mA   -120.9mA   -95.91mA
-1.19V    -79.83mA   -92.52mA   -66.44mA
-1.055V   -56.49mA   -68.85mA   -42.87mA
-930mV    -37.22mA   -48.83mA   -24.23mA
-825mV    -23.15mA   -33.69mA   -11.62mA
-735mV    -13.05mA   -22.2mA    -4.047mA
-630mV    -4.546mA   -11.14mA   -460.9uA
-530mV    -851.6uA   -4.034mA   -22.09uA
-440mV    -107.1uA   -1.048mA   -763.5nA
-315mV    -3.31uA    -88.5uA    -3.906nA
1.5V      230pA      151.5nA    38.95pA
[Pulldown]
| TXB0104_IO_A_OS_15A
|   Voltage   I(typ)   I(min)   I(max)
-1.5V     -26.94mA   -24.96mA   -32.62mA
-1.2V     -24.55mA   -22.76mA   -29.8mA
-925mV    -21.59mA   -20.09mA   -26.09mA
-730mV    -18.87mA   -17.7mA    -22.42mA
-550mV    -15.43mA   -14.86mA   -17.41mA
-370mV    -10.66mA   -10.78mA   -11.83mA
215mV     5.293mA    5.507mA    5.761mA
460mV     10.78mA    11.18mA    11.5mA
675mV     14.53mA    15.11mA    14.95mA
900mV     17.01mA    17.89mA    16.6mA
1.16V     18.23mA    19.44mA    17.29mA
3V        22.11mA    24.15mA    19.99mA
[Pullup]
| TXB0104_IO_A_OS_15A
|   Voltage   I(typ)   I(min)   I(max)
-1.5V     34.09mA    35.03mA    37.84mA
-585mV    12.99mA    13.24mA    14.6mA
-245mV    5.604mA    5.63mA     6.871mA
-130mV    3.164mA    3.134mA    3.652mA
70mV      -1.101mA   -1.155mA   -1.257mA
345mV     -6.191mA   -6.27mA    -6.995mA
595mV     -9.752mA   -9.87mA    -10.82mA
720mV     -11.04mA   -11.21mA   -12.08mA
850mV     -11.99mA   -12.22mA   -12.9mA
1.155V    -13.09mA   -13.45mA   -13.87mA
1.95V     -14.53mA   -15.04mA   -15.19mA
3V        -15.68mA   -16.41mA   -16.21mA
[Ramp]
| TXB0104_IO_A_OS_15A
| variable   typ   min   max
dV/dt_r   0.37/6.92E-10   0.36/7.70E-10   0.40/6.75E-10
dV/dt_f   0.46/1.35E-09   0.44/1.27E-09   0.48/1.33E-09
R_load = 50
[Rising Waveform]
| TXB0104_IO_A_OS_15A
R_fixture =   50
C_fixture =   0
L_fixture =   0
V_fixture =   0
V_fixture_min = 0
V_fixture_max = 0
|   Time   V(typ)   V(min)   V(max)
0s        7.178mV    6.143mV    7.749mV
1.87ns    -1.321mV   3.553mV    2.177mV
2.17ns    7.055mV    75.46mV    -3.143mV
2.39ns    68.94mV    176.4mV    3.228mV
2.635ns   198.9mV    299.5mV    87.98mV
2.955ns   390.2mV    447.7mV    312.9mV
3.39ns    539.4mV    553mV      534.2mV
3.855ns   592.3mV    583.4mV    624.4mV
4.53ns    607.1mV    592.8mV    660.9mV
39.96ns   610.2mV    595.5mV    662.8mV
[Falling Waveform]
| TXB0104_IO_A_OS_15A
R_fixture =   50
C_fixture =   0
L_fixture =   0
V_fixture =   1.5
V_fixture_min = 1.4
V_fixture_max = 1.6
|   Time   V(typ)   V(min)   V(max)
0s        1.491V     1.393V     1.591V
2.28ns    1.496V     1.393V     1.595V
2.52ns    1.495V     1.356V     1.597V
2.845ns   1.434V     1.234V     1.586V
3.15ns    1.323V     1.107V     1.513V
3.65ns    1.129V     923.4mV    1.316V
4.265ns   928.3mV    771.2mV    1.072V
5.13ns    786.5mV    689mV      878.7mV
6.27ns    742.3mV    664.1mV    811.9mV
39.96ns   733.5mV    658.2mV    797mV
[Rising Waveform]
| TXB0104_IO_A_OS_15A
R_fixture =   50
C_fixture =   0
L_fixture =   0
V_fixture =   1.5
V_fixture_min = 1.4
V_fixture_max = 1.6
|   Time   V(typ)   V(min)   V(max)
0s        733.5mV    658mV      796.9mV
1.48ns    705.7mV    648.9mV    734.2mV
1.975ns   764.4mV    755mV      769.9mV
2.17ns    853.4mV    899.1mV    834mV
2.355ns   1.006V     1.056V     944.3mV
2.65ns    1.277V     1.231V     1.251V
2.95ns    1.423V     1.33V      1.499V
3.185ns   1.472V     1.37V      1.569V
3.64ns    1.494V     1.392V     1.593V
39.96ns   1.491V     1.393V     1.591V
[Falling Waveform]
| TXB0104_IO_A_OS_15A
R_fixture =   50
C_fixture =   0
L_fixture =   0
V_fixture =   0
V_fixture_min = 0
V_fixture_max = 0
|   Time   V(typ)   V(min)   V(max)
0s        610.2mV    595.5mV    662.8mV
1.585ns   627.1mV    601.7mV    697.3mV
2.145ns   589.2mV    560.9mV    661mV
2.395ns   541.6mV    503.4mV    608.7mV
2.61ns    476.3mV    399.1mV    539.3mV
2.895ns   328.2mV    234.6mV    418.3mV
3.17ns    184mV      136.9mV    258.8mV
3.59ns    70.54mV    59mV       80.02mV
4.185ns   16.65mV    16.47mV    11.54mV
39.96ns   7.178mV    6.143mV    7.749mV
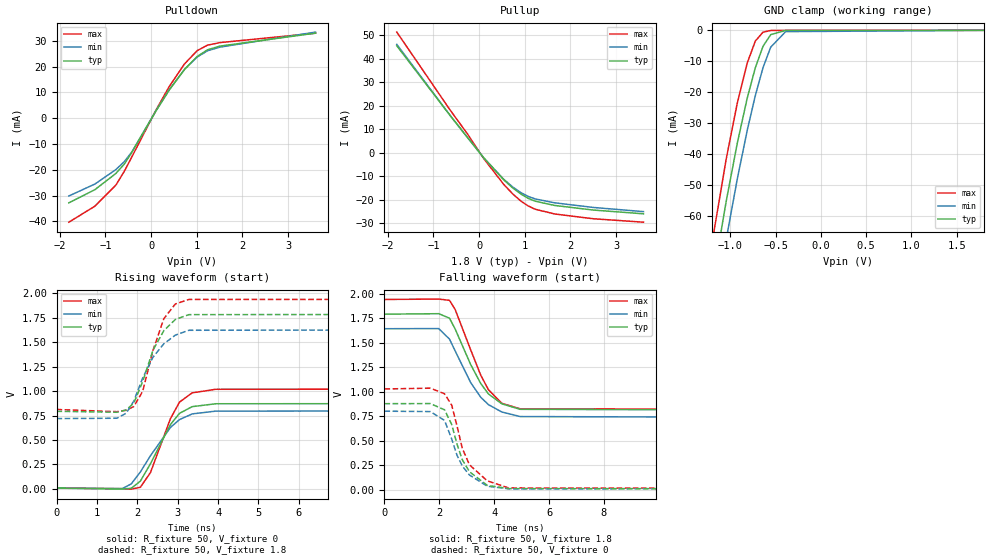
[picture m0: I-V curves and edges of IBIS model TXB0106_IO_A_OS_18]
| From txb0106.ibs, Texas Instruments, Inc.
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[Model]   TXB0106_IO_A_OS_18
Model_type  I/O
Vinl=0.5775
Vinh=1.2675
Enable   Active-High
Vref =   0
Rref =   1E6
Cref =   15p
Vmeas =   0.9
| variable   typ   min   max
C_comp   5.08pF   4.35pF   5.49pF
| C_pullup   5.65pF   3.90pF   7.15pF
| C_pulldown   5.71pF   4.95pF   6.87pF
| C_tri-state   5.08pF   4.35pF   5.49pF
[Temperature Range]   40   100   -40
| Ambient temperature   25   85   -40
[Voltage range]   1.8   1.65   1.95
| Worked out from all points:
|   slope of the pulldown table from 0 to 0.27 V, typ, clamps not added: 34.2 ohm
|   slope of the pullup table from 0 to 0.27 V, typ, clamps not added: 42.9 ohm
|   GND clamp passes 1 mA (typ) near -0.54 V on its own axis
|   rising waveform, R_fixture 50, V_fixture 0: 20-80 % time 666ps typ, 789ps min, 570ps max; typ from 0.008 V to 0.878 V
|   falling waveform, R_fixture 50, V_fixture 1.8: 20-80 % time 1.09ns typ, 1.13ns min, 1ns max; typ from 1.79 V to 0.793 V
|   rising waveform, R_fixture 50, V_fixture 1.8: 20-80 % time 563ps typ, 679ps min, 462ps max; typ from 0.793 V to 1.79 V
|   falling waveform, R_fixture 50, V_fixture 0: 20-80 % time 700ps typ, 749ps min, 717ps max; typ from 0.878 V to 0.008 V
[GND Clamp]
| TXB0104_IO_A_OS_18
|   Voltage   I(typ)   I(min)   I(max)
-1.8V     -207.5mA   -218.1mA   -201mA
-1.46V    -132.7mA   -145mA     -121.5mA
-1.31V    -102.4mA   -115.1mA   -89.8mA
-1.175V   -77.15mA   -89.82mA   -63.69mA
-1.045V   -54.88mA   -67.19mA   -41.27mA
-925mV    -36.52mA   -48.09mA   -23.57mA
-815mV    -21.94mA   -32.35mA   -10.6mA
-725mV    -12.07mA   -21.04mA   -3.463mA
-640mV    -5.163mA   -12.06mA   -596.7uA
-555mV    -1.39mA    -5.436mA   -50.79uA
-390mV    -28.8uA    -418.5uA   -98.22nA
1.8V      270.4pA    109.4nA    46.6pA
[Pulldown]
| TXB0104_IO_A_OS_18
|   Voltage   I(typ)   I(min)   I(max)
-1.8V     -32.79mA   -30.14mA   -40.29mA
-1.23V    -27.69mA   -25.51mA   -34.08mA
-770mV    -21.4mA    -19.9mA    -25.89mA
-590mV    -17.85mA   -16.89mA   -20.69mA
-425mV    -13.34mA   -13.19mA   -15.11mA
110mV     2.891mA    2.994mA    3.252mA
400mV     10.99mA    11.12mA    12.35mA
730mV     18.85mA    18.86mA    21mA
1.01V     23.94mA    23.73mA    26.19mA
1.235V    26.5mA     26.12mA    28.3mA
1.505V    27.92mA    27.53mA    29.28mA
3.6V      32.94mA    33.36mA    32.94mA
[Pullup]
| TXB0104_IO_A_OS_18
|   Voltage   I(typ)   I(min)   I(max)
-1.8V     45.57mA    46.17mA    51.4mA
-625mV    15.73mA    15.78mA    18.04mA
-250mV    6.56mA     6.477mA    8.008mA
110mV     -2.218mA   -2.247mA   -2.594mA
545mV     -11.51mA   -11.28mA   -13.47mA
740mV     -14.92mA   -14.51mA   -17.47mA
920mV     -17.53mA   -16.92mA   -20.52mA
1.07V     -19.24mA   -18.44mA   -22.48mA
1.225V    -20.5mA    -19.53mA   -23.91mA
1.655V    -22.33mA   -21.21mA   -25.96mA
2.505V    -24.3mA    -23.19mA   -27.99mA
3.6V      -25.88mA   -24.96mA   -29.45mA
[Ramp]
| TXB0104_IO_A_OS_18
| variable   typ   min   max
dV/dt_r   0.53/6.77E-10   0.48/7.98E-10   0.62/5.80E-10
dV/dt_f   0.60/1.10E-09   0.56/1.14E-09   0.68/1.01E-09
R_load = 50
[Rising Waveform]
| TXB0104_IO_A_OS_18
R_fixture =   50
C_fixture =   0
L_fixture =   0
V_fixture =   0
V_fixture_min = 0
V_fixture_max = 0
|   Time   V(typ)   V(min)   V(max)
0s        8.233mV    6.965mV    8.88mV
1.63ns    -917.4uV   3.536mV    2.048mV
1.85ns    6.091mV    50.85mV    -2.77mV
2.075ns   78.96mV    172.4mV    16.38mV
2.325ns   256.2mV    338.4mV    166mV
2.82ns    657.6mV    627.7mV    716.9mV
3.045ns   772.1mV    708.6mV    887.3mV
3.36ns    840.7mV    766.3mV    981.6mV
3.945ns   870.1mV    795mV      1.018V
39.97ns   877.9mV    801.6mV    1.028V
[Falling Waveform]
| TXB0104_IO_A_OS_18
R_fixture =   50
C_fixture =   0
L_fixture =   0
V_fixture =   1.8
V_fixture_min = 1.65
V_fixture_max = 1.95
|   Time   V(typ)   V(min)   V(max)
0s        1.79V      1.642V     1.94V
1.98ns    1.795V     1.643V     1.944V
2.37ns    1.749V     1.536V     1.931V
2.575ns   1.64V      1.417V     1.839V
3.14ns    1.278V     1.094V     1.428V
3.51ns    1.083V     943.4mV    1.168V
3.79ns    977.2mV    868.3mV    1.02V
4.28ns    876.3mV    793mV      881.7mV
4.945ns   820.6mV    746.8mV    825.9mV
39.97ns   793.1mV    718.8mV    811.7mV
[Rising Waveform]
| TXB0104_IO_A_OS_18
R_fixture =   50
C_fixture =   0
L_fixture =   0
V_fixture =   1.8
V_fixture_min = 1.65
V_fixture_max = 1.95
|   Time   V(typ)   V(min)   V(max)
0s        792.9mV    718.7mV    811.7mV
1.495ns   783mV      722.1mV    789.3mV
1.725ns   806.7mV    773.4mV    803.7mV
1.915ns   877.4mV    899.3mV    842.3mV
2.135ns   1.099V     1.135V     998.6mV
2.39ns    1.419V     1.347V     1.417V
2.655ns   1.616V     1.482V     1.738V
2.94ns    1.731V     1.571V     1.889V
3.275ns   1.781V     1.621V     1.936V
39.97ns   1.79V      1.642V     1.94V
[Falling Waveform]
| TXB0104_IO_A_OS_18
R_fixture =   50
C_fixture =   0
L_fixture =   0
V_fixture =   0
V_fixture_min = 0
V_fixture_max = 0
|   Time   V(typ)   V(min)   V(max)
0s        877.9mV    801.6mV    1.028V
1.67ns    879.2mV    797.6mV    1.036V
2.19ns    815.6mV    707.6mV    979.1mV
2.45ns    666.5mV    518.5mV    864mV
2.645ns   465.1mV    352.2mV    649.5mV
2.84ns    305.5mV    241.8mV    420.8mV
3.1ns     184mV      151mV      254.4mV
3.75ns    45.58mV    36.91mV    90.94mV
4.53ns    12.76mV    10.47mV    19.31mV
39.97ns   8.233mV    6.965mV    8.88mV
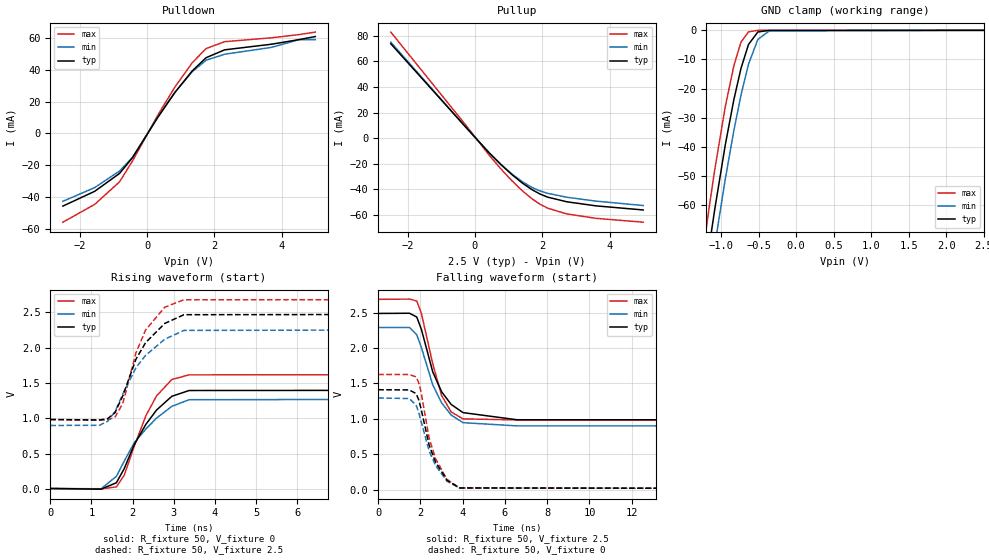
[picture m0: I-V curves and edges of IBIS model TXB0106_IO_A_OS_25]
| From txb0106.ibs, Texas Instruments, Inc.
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[Model]   TXB0106_IO_A_OS_25
Model_type  I/O
Vinl=0.805
Vinh=1.755
Enable   Active-High
Vref =   0
Rref =   1e6
Cref =   15p
Vmeas =   1.25
| variable   typ   min   max
C_comp   4.97pF   4.28pF   5.31pF
| C_pullup   5.15pF   3.68pF   6.59pF
| C_pulldown   5.31pF   4.81pF   6.14pF
| C_tri-state   4.97pF   4.28pF   5.31pF
[Temperature Range]   40   100   -40
| Ambient temperature   25   85   -40
[Voltage range]   2.5   2.3   2.7
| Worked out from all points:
|   slope of the pulldown table from 0 to 0.375 V, typ, clamps not added: 29.9 ohm
|   slope of the pullup table from 0 to 0.375 V, typ, clamps not added: 35 ohm
|   GND clamp passes 1 mA (typ) near -0.54 V on its own axis
|   rising waveform, R_fixture 50, V_fixture 0: 20-80 % time 803ps typ, 954ps min, 679ps max; typ from 0.011 V to 1.41 V
|   falling waveform, R_fixture 50, V_fixture 2.5: 20-80 % time 1.1ns typ, 1.06ns min, 852ps max; typ from 2.49 V to 0.986 V
|   rising waveform, R_fixture 50, V_fixture 2.5: 20-80 % time 746ps typ, 897ps min, 603ps max; typ from 0.986 V to 2.49 V
|   falling waveform, R_fixture 50, V_fixture 0: 20-80 % time 844ps typ, 893ps min, 789ps max; typ from 1.41 V to 0.011 V
[GND Clamp]
| TXB0104_IO_A_OS_25
|   Voltage   I(typ)   I(min)   I(max)
-2.5V     -378.5mA   -383.3mA   -384.2mA
-1.245V   -90.05mA   -102.8mA   -76.94mA
-1.22V    -85.39mA   -98.11mA   -72.14mA
-1.155V   -73.61mA   -86.27mA   -60.08mA
-1.085V   -61.52mA   -74mA      -47.87mA
-945mV    -39.44mA   -51.17mA   -26.3mA
-830mV    -23.79mA   -34.41mA   -12.15mA
-735mV    -13.06mA   -22.23mA   -4.051mA
-635mV    -4.853mA   -11.61mA   -525.3uA
-510mV    -558.6uA   -3.11mA    -10.96uA
-360mV    -12.45uA   -230.2uA   -27.55nA
2.5V      380.1pA    138.6nA    65.01pA
[Pulldown]
| TXB0104_IO_A_OS_25
|   Voltage   I(typ)   I(min)   I(max)
-2.5V     -45.84mA   -42.83mA   -56mA
-1.555V   -36.51mA   -34.18mA   -44.76mA
-815mV    -25.22mA   -23.71mA   -30.5mA
-425mV    -15.07mA   -14.95mA   -17.12mA
315mV     9.991mA    10.2mA     11.32mA
830mV     25.9mA     26mA       29.34mA
1.345V    39.5mA     38.98mA    44.64mA
1.755V    47.77mA    46.19mA    53.53mA
2.305V    52.74mA    49.96mA    57.87mA
3.7V      56.29mA    54.29mA    60.35mA
4.51V     59.16mA    59.13mA    62.34mA
5V        61.12mA    59.21mA    63.94mA
[Pullup]
| TXB0104_IO_A_OS_25
|   Voltage   I(typ)   I(min)   I(max)
-2.5V     73.65mA    74.83mA    82.76mA
-270mV    8.522mA    8.482mA    10.1mA
420mV     -11.37mA   -11.39mA   -13.2mA
770mV     -20.59mA   -20.4mA    -23.97mA
1.1V      -28.5mA    -27.95mA   -33.29mA
1.405V    -34.97mA   -33.92mA   -41mA
1.69V     -40.11mA   -38.4mA    -47.22mA
1.93V     -43.56mA   -41.18mA   -51.5mA
2.16V     -46.01mA   -43.04mA   -54.63mA
2.73V     -49.65mA   -46.11mA   -59.12mA
3.595V    -52.82mA   -49.12mA   -62.56mA
5V        -56.03mA   -52.57mA   -65.57mA
[Ramp]
| TXB0104_IO_A_OS_25
| variable   typ   min   max
dV/dt_r   0.85/8.09E-10   0.78/9.59E-10   0.98/6.83E-10
dV/dt_f   0.90/1.10E-09   0.83/1.07E-09   1.02/8.56E-10
R_load = 50
[Rising Waveform]
| TXB0104_IO_A_OS_25
R_fixture =   50
C_fixture =   0
L_fixture =   0
V_fixture =   0
V_fixture_min = 0
V_fixture_max = 0
|   Time   V(typ)   V(min)   V(max)
0s        10.77mV    9.127mV    11.5mV
1.235ns   1.108mV    7.079mV    3.665mV
1.605ns   92.14mV    182.7mV    33.78mV
1.795ns   291.3mV    396.9mV    198.1mV
2.04ns    632.6mV    658.4mV    609.2mV
2.32ns    916.1mV    850.8mV    1.038V
2.58ns    1.119V     1.005V     1.319V
2.95ns    1.313V     1.171V     1.55V
3.37ns    1.395V     1.265V     1.616V
39.94ns   1.412V     1.295V     1.627V
[Falling Waveform]
| TXB0104_IO_A_OS_25
R_fixture =   50
C_fixture =   0
L_fixture =   0
V_fixture =   2.5
V_fixture_min = 2.3
V_fixture_max = 2.7
|   Time   V(typ)   V(min)   V(max)
0s        2.488V     2.29V      2.687V
1.48ns    2.491V     2.29V      2.691V
1.825ns   2.438V     2.188V     2.664V
2.045ns   2.263V     2.007V     2.488V
2.58ns    1.665V     1.482V     1.779V
3ns       1.384V     1.227V     1.331V
3.455ns   1.204V     1.054V     1.098V
4.015ns   1.089V     947.3mV    1.001V
6.57ns    988.3mV    901.9mV    985.7mV
39.94ns   985.5mV    901mV      985.2mV
[Rising Waveform]
| TXB0104_IO_A_OS_25
R_fixture =   50
C_fixture =   0
L_fixture =   0
V_fixture =   2.5
V_fixture_min = 2.3
V_fixture_max = 2.7
|   Time   V(typ)   V(min)   V(max)
0s        985.5mV    901mV      985.2mV
1.19ns    978.6mV    903.4mV    975.2mV
1.395ns   997.4mV    960mV      979.7mV
1.57ns    1.081V     1.097V     1.018V
1.76ns    1.32V      1.345V     1.21V
2.08ns    1.838V     1.718V     1.928V
2.315ns   2.072V     1.892V     2.251V
2.78ns    2.343V     2.12V      2.572V
3.245ns   2.466V     2.244V     2.677V
39.94ns   2.488V     2.29V      2.687V
[Falling Waveform]
| TXB0104_IO_A_OS_25
R_fixture =   50
C_fixture =   0
L_fixture =   0
V_fixture =   0
V_fixture_min = 0
V_fixture_max = 0
|   Time   V(typ)   V(min)   V(max)
0s        1.412V     1.295V     1.627V
1.47ns    1.409V     1.288V     1.627V
1.79ns    1.358V     1.195V     1.593V
1.905ns   1.28V      1.105V     1.522V
2.02ns    1.156V     979.2mV    1.393V
2.41ns    631.2mV    549.6mV    728.8mV
2.715ns   390mV      343mV      439.4mV
3.26ns    133.7mV    121.1mV    145.4mV
3.85ns    26.55mV    26.08mV    25.98mV
39.94ns   10.77mV    9.128mV    11.5mV
